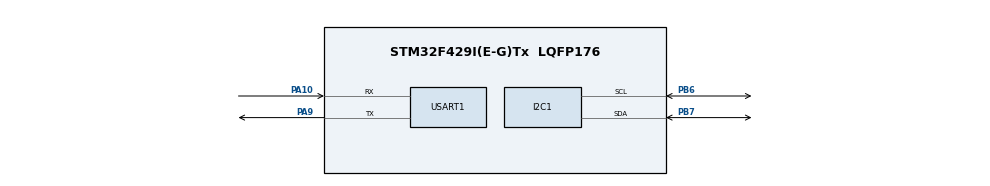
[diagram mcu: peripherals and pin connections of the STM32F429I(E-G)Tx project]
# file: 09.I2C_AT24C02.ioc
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Mcu.Family=STM32F4
Mcu.Name=STM32F429I(E-G)Tx
Mcu.Package=LQFP176
NVIC.PriorityGroup=NVIC_PRIORITYGROUP_4
PA10.Mode=Asynchronous
PA10.Signal=USART1_RX
PA9.Mode=Asynchronous
PA9.Signal=USART1_TX
PB6.Mode=I2C
PB6.Signal=I2C1_SCL
PB7.Mode=I2C
PB7.Signal=I2C1_SDA
PH0/OSC_IN.Mode=HSE-External-Oscillator
PH0/OSC_IN.Signal=RCC_OSC_IN
PH1/OSC_OUT.Mode=HSE-External-Oscillator
PH1/OSC_OUT.Signal=RCC_OSC_OUT
ProjectManager.HeapSize=0x200
ProjectManager.StackSize=0x400
ProjectManager.TargetToolchain=STM32CubeIDE
RCC.AHBFreq_Value=16000000
RCC.APB1Freq_Value=16000000
RCC.APB2Freq_Value=16000000
RCC.CortexFreq_Value=16000000
RCC.HSE_VALUE=25000000
RCC.HSI_VALUE=16000000
RCC.LSE_VALUE=32768
RCC.SYSCLKFreq_VALUE=16000000
RCC.VCOOutputFreq_Value=192000000
USART1.VirtualMode=VM_ASYNC
board=custom

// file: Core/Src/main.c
/**
  ******************************************************************************
  * File Name          : main.c
  * Description        : Main program body
  ******************************************************************************
  *
  * COPYRIGHT(c) 2016 STMicroelectronics
  *
  * Redistribution and use in source and binary forms, with or without modification,
  * are permitted provided that the following conditions are met:
  *   1. Redistributions of source code must retain the above copyright notice,
  *      this list of conditions and the following disclaimer.
  *   2. Redistributions in binary form must reproduce the above copyright notice,
  *      this list of conditions and the following disclaimer in the documentation
  *      and/or other materials provided with the distribution.
  *   3. Neither the name of STMicroelectronics nor the names of its contributors
  *      may be used to endorse or promote products derived from this software
  *      without specific prior written permission.
  *
  * THIS SOFTWARE IS PROVIDED BY THE COPYRIGHT HOLDERS AND CONTRIBUTORS "AS IS"
  * AND ANY EXPRESS OR IMPLIED WARRANTIES, INCLUDING, BUT NOT LIMITED TO, THE
  * IMPLIED WARRANTIES OF MERCHANTABILITY AND FITNESS FOR A PARTICULAR PURPOSE ARE
  * DISCLAIMED. IN NO EVENT SHALL THE COPYRIGHT HOLDER OR CONTRIBUTORS BE LIABLE
  * FOR ANY DIRECT, INDIRECT, INCIDENTAL, SPECIAL, EXEMPLARY, OR CONSEQUENTIAL
  * DAMAGES (INCLUDING, BUT NOT LIMITED TO, PROCUREMENT OF SUBSTITUTE GOODS OR
  * SERVICES; LOSS OF USE, DATA, OR PROFITS; OR BUSINESS INTERRUPTION) HOWEVER
  * CAUSED AND ON ANY THEORY OF LIABILITY, WHETHER IN CONTRACT, STRICT LIABILITY,
  * OR TORT (INCLUDING NEGLIGENCE OR OTHERWISE) ARISING IN ANY WAY OUT OF THE USE
  * OF THIS SOFTWARE, EVEN IF ADVISED OF THE POSSIBILITY OF SUCH DAMAGE.
  *
  ******************************************************************************
  */
#include "stm32f4xx_hal.h"
#include "i2c.h"
#include "usart.h"
#include "gpio.h"

/* USER CODE BEGIN Includes */
#include <stdio.h>
#include <string.h>
/* USER CODE END Includes */

/* USER CODE BEGIN PV */
/* Private variables ---------------------------------------------------------*/
#define ADDR_24LCxx_Write 0xA0
#define ADDR_24LCxx_Read 0xA1
uint8_t WriteBuffer[256],ReadBuffer[256];
/* USER CODE END PV */

void SystemClock_Config(void);

/* USER CODE BEGIN PFP */
/* Private function prototypes -----------------------------------------------*/

/* USER CODE END PFP */

/* USER CODE BEGIN 0 */
/**
  * @brief  Retargets the C library printf function to the USART.
  * @param  None
  * @retval None
  */
int fputc(int ch, FILE *f)
{
  /* write a character to the uart1 and Loop until the end of transmission */
  HAL_UART_Transmit(&huart1, (uint8_t *)&ch, 1, 0xFFFF);

  return ch;
}

/* USER CODE END 0 */

int main(void)
{

  /* USER CODE BEGIN 1 */
	uint16_t i;
  /* USER CODE END 1 */

  /* MCU Configuration----------------------------------------------------------*/

  /* Reset of all peripherals, Initializes the Flash interface and the Systick. */
  HAL_Init();

  /* Configure the system clock */
  SystemClock_Config();

  /* Initialize all configured peripherals */
  MX_GPIO_Init();
  MX_I2C1_Init();
  MX_USART1_UART_Init();

  /* USER CODE BEGIN 2 */
	printf("\r\n***************I2C Example*******************************\r\n");
	for(i=0; i<256; i++)
		WriteBuffer[i]=i;	 /* WriteBuffer init */
	/* wrinte date to EEPROM */
	if(HAL_I2C_Mem_Write(&hi2c1, ADDR_24LCxx_Write, 0, I2C_MEMADD_SIZE_8BIT,WriteBuffer,sizeof(WriteBuffer), 0x10) == HAL_OK)
		printf("\r\n EEPROM 24C02 Write Test OK \r\n");
	else
		printf("\r\n EEPROM 24C02 Write Test False \r\n");

	/* read date from EEPROM */
	HAL_I2C_Mem_Read(&hi2c1, ADDR_24LCxx_Read, 0, I2C_MEMADD_SIZE_8BIT,ReadBuffer,sizeof(ReadBuffer), 0x10);

	if(memcmp(WriteBuffer,ReadBuffer,sizeof(WriteBuffer)) == 0 ) /* check date */
		printf("\r\n EEPROM 24C02 Read Test OK\r\n");
	else
		printf("\r\n EEPROM 24C02 Read Test False\r\n");

  /* USER CODE END 2 */

  /* Infinite loop */
  while (1)
  {

  }

}

/** System Clock Configuration
*/
void SystemClock_Config(void)
{

  RCC_OscInitTypeDef RCC_OscInitStruct;
  RCC_ClkInitTypeDef RCC_ClkInitStruct;

  __PWR_CLK_ENABLE();

  __HAL_PWR_VOLTAGESCALING_CONFIG(PWR_REGULATOR_VOLTAGE_SCALE1);

  RCC_OscInitStruct.OscillatorType = RCC_OSCILLATORTYPE_HSE;
  RCC_OscInitStruct.HSEState = RCC_HSE_ON;
  RCC_OscInitStruct.PLL.PLLState = RCC_PLL_ON;
  RCC_OscInitStruct.PLL.PLLSource = RCC_PLLSOURCE_HSE;
  RCC_OscInitStruct.PLL.PLLM = 5;
  RCC_OscInitStruct.PLL.PLLN = 210;
  RCC_OscInitStruct.PLL.PLLP = RCC_PLLP_DIV2;
  RCC_OscInitStruct.PLL.PLLQ = 4;
  HAL_RCC_OscConfig(&RCC_OscInitStruct);

  RCC_ClkInitStruct.ClockType = RCC_CLOCKTYPE_SYSCLK|RCC_CLOCKTYPE_PCLK1
                              |RCC_CLOCKTYPE_PCLK2;
  RCC_ClkInitStruct.SYSCLKSource = RCC_SYSCLKSOURCE_PLLCLK;
  RCC_ClkInitStruct.AHBCLKDivider = RCC_SYSCLK_DIV1;
  RCC_ClkInitStruct.APB1CLKDivider = RCC_HCLK_DIV4;
  RCC_ClkInitStruct.APB2CLKDivider = RCC_HCLK_DIV2;
  HAL_RCC_ClockConfig(&RCC_ClkInitStruct, FLASH_LATENCY_5);

  HAL_SYSTICK_Config(HAL_RCC_GetHCLKFreq()/1000);

  HAL_SYSTICK_CLKSourceConfig(SYSTICK_CLKSOURCE_HCLK);

  /* SysTick_IRQn interrupt configuration */
  HAL_NVIC_SetPriority(SysTick_IRQn, 0, 0);
}

/************************ (C) COPYRIGHT STMicroelectronics *****END OF FILE****/
